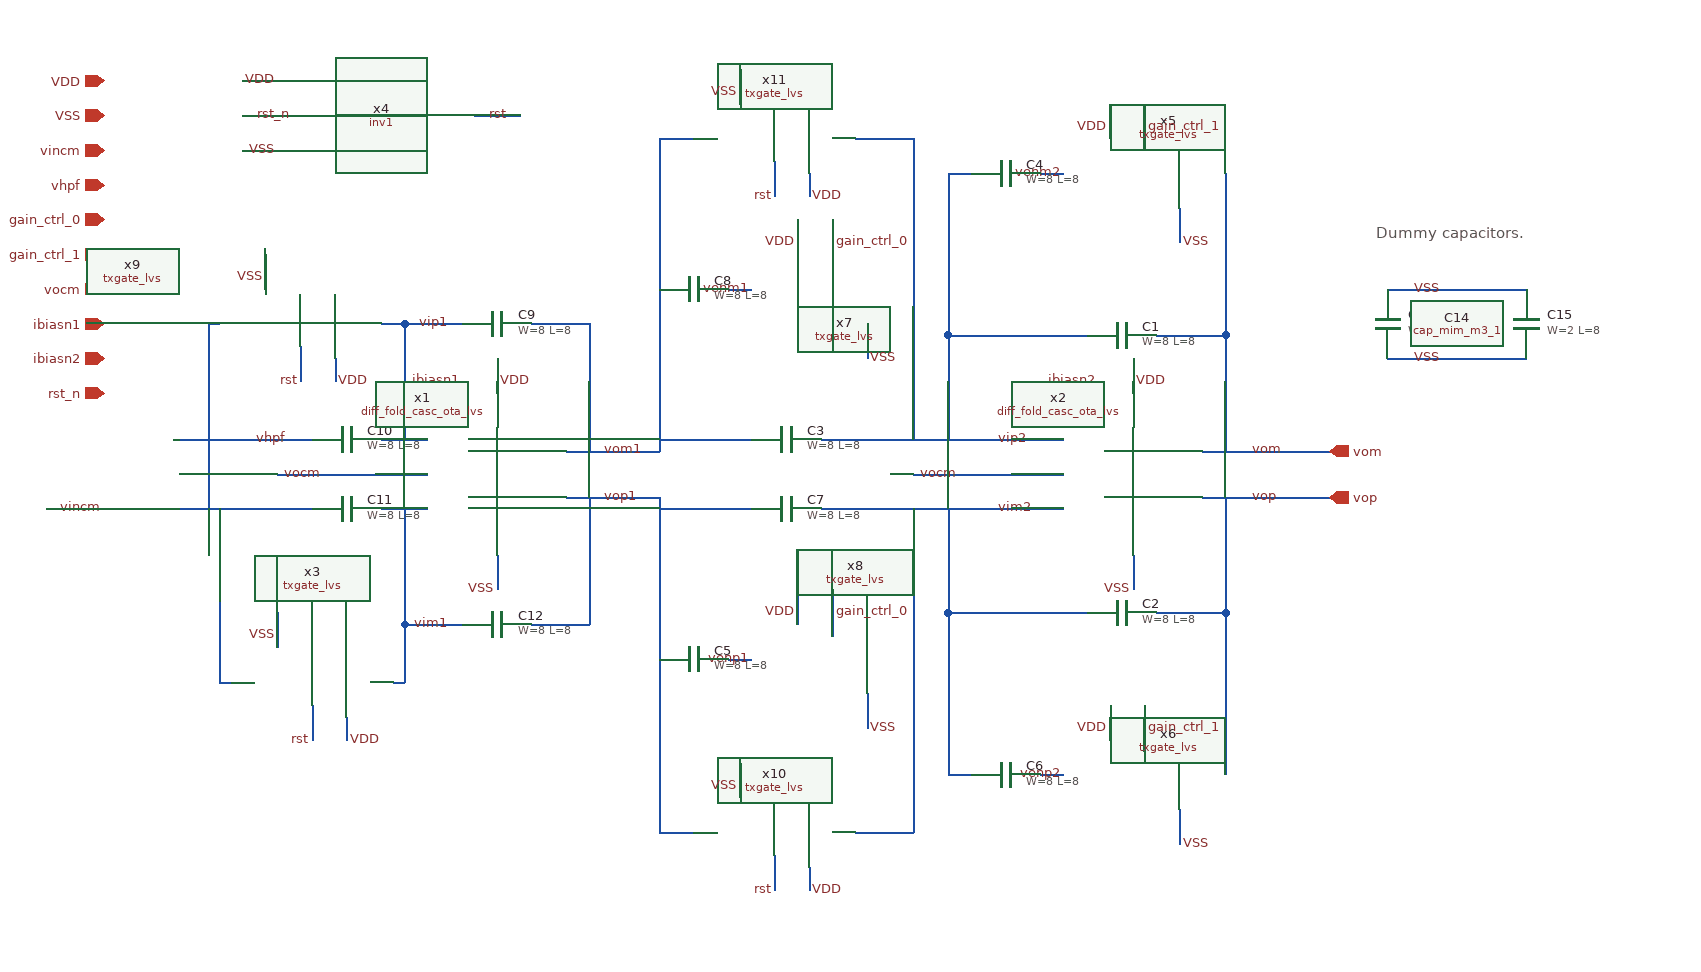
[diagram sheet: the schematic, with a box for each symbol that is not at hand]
v {xschem version=2.9.9 file_version=1.2 }
G {}
K {}
V {}
S {}
E {}
T {Dummy capacitors.} 1230 -710 0 0 0.4 0.4 {}
N 1040 -610 1100 -610 { lab=vom}
N 1100 -610 1100 -510 { lab=vom}
N 1080 -470 1190 -470 { lab=vop}
N 1080 -510 1190 -510 { lab=vom}
N 860 -610 980 -610 { lab=vip2}
N 860 -610 860 -520 { lab=vip2}
N 860 -750 880 -750 { lab=vip2}
N 860 -750 860 -610 { lab=vip2}
N 1100 -750 1100 -610 { lab=vom}
N 750 -520 960 -520 { lab=vip2}
N 830 -650 830 -520 { lab=vip2}
N 1040 -370 1100 -370 { lab=vop}
N 1100 -470 1100 -370 { lab=vop}
N 860 -370 980 -370 { lab=vim2}
N 860 -460 860 -370 { lab=vim2}
N 860 -230 880 -230 { lab=vim2}
N 860 -370 860 -230 { lab=vim2}
N 1100 -370 1100 -230 { lab=vop}
N 750 -460 960 -460 { lab=vim2}
N 830 -460 830 -330 { lab=vim2}
N 370 -520 410 -520 { lab=vip1}
N 370 -460 410 -460 { lab=vim1}
N 390 -460 390 -360 { lab=vim1}
N 390 -360 440 -360 { lab=vim1}
N 390 -620 390 -520 { lab=vip1}
N 390 -620 440 -620 { lab=vip1}
N 280 -490 410 -490 { lab=vocm}
N 500 -620 550 -620 { lab=vom1}
N 550 -620 550 -510 { lab=vom1}
N 500 -360 550 -360 { lab=vop1}
N 550 -470 550 -360 { lab=vop1}
N 530 -510 610 -510 { lab=vom1}
N 530 -470 610 -470 { lab=vop1}
N 190 -520 310 -520 { lab=vhpf}
N 80 -460 310 -460 { lab=vincm}
N 830 -490 960 -490 { lab=vocm}
N 610 -520 690 -520 { lab=vom1}
N 610 -460 690 -460 { lab=vop1}
N 610 -650 610 -510 { lab=vom1}
N 610 -470 610 -330 { lab=vop1}
N 940 -750 960 -750 { lab=venm2}
N 1030 -810 1030 -770 { lab=gain_ctrl_1}
N 1060 -720 1060 -690 { lab=VSS}
N 1000 -810 1000 -780 { lab=VDD}
N 940 -230 960 -230 { lab=venp2}
N 1030 -290 1030 -250 { lab=gain_ctrl_1}
N 1060 -200 1060 -170 { lab=VSS}
N 1000 -290 1000 -260 { lab=VDD}
N 760 -710 760 -670 { lab=gain_ctrl_0}
N 790 -620 790 -590 { lab=VSS}
N 730 -710 730 -680 { lab=VDD}
N 670 -650 690 -650 { lab=venm1}
N 760 -390 760 -350 { lab=gain_ctrl_0}
N 790 -300 790 -270 { lab=VSS}
N 730 -390 730 -360 { lab=VDD}
N 670 -330 690 -330 { lab=venp1}
N 400 -570 440 -570 { lab=ibiasn1}
N 470 -590 470 -560 { lab=VDD}
N 470 -420 470 -390 { lab=VSS}
N 950 -570 990 -570 { lab=ibiasn2}
N 1020 -590 1020 -560 { lab=VDD}
N 1020 -420 1020 -390 { lab=VSS}
N 1240 -650 1350 -650 { lab=VSS}
N 1240 -590 1350 -590 { lab=VSS}
N 380 -310 390 -310 { lab=vim1}
N 230 -310 240 -310 { lab=vincm}
N 280 -370 280 -340 { lab=VSS}
N 340 -280 340 -260 { lab=VDD}
N 310 -290 310 -260 { lab=rst}
N 450 -800 490 -800 { lab=rst}
N 250 -830 290 -830 { lab=VDD}
N 250 -770 290 -770 { lab=VSS}
N 250 -800 290 -800 { lab=rst_n}
N 390 -360 390 -310 { lab=vim1}
N 230 -460 230 -310 { lab=vincm}
N 370 -620 380 -620 { lab=vip1}
N 220 -620 230 -620 { lab=vincm}
N 270 -680 270 -650 { lab=VSS}
N 330 -590 330 -570 { lab=VDD}
N 300 -600 300 -570 { lab=rst}
N 380 -620 390 -620 { lab=vip1}
N 220 -620 220 -460 { lab=vincm}
N 780 -180 790 -180 { lab=vim2}
N 630 -180 640 -180 { lab=vop1}
N 680 -240 680 -210 { lab=VSS}
N 740 -150 740 -130 { lab=VDD}
N 710 -160 710 -130 { lab=rst}
N 790 -180 800 -180 { lab=vim2}
N 800 -180 830 -180 { lab=vim2}
N 830 -330 830 -180 { lab=vim2}
N 610 -180 630 -180 { lab=vop1}
N 610 -330 610 -180 { lab=vop1}
N 780 -780 790 -780 { lab=vip2}
N 630 -780 640 -780 { lab=vom1}
N 680 -840 680 -810 { lab=VSS}
N 740 -750 740 -730 { lab=VDD}
N 710 -760 710 -730 { lab=rst}
N 790 -780 800 -780 { lab=vip2}
N 800 -780 830 -780 { lab=vip2}
N 830 -780 830 -650 { lab=vip2}
N 610 -780 630 -780 { lab=vom1}
N 610 -780 610 -650 { lab=vom1}
N 1350 -650 1360 -650 {}
N 1350 -590 1360 -590 {}
C {devices/title.sym} 160 -30 0 0 {name=l1 author="Nikhil Poole"}
C {devices/lab_wire.sym} 1120 -510 0 1 {name=l7 sig_type=std_logic lab=vom}
C {devices/lab_wire.sym} 1120 -470 0 1 {name=l8 sig_type=std_logic lab=vop}
C {devices/lab_wire.sym} 430 -620 0 0 {name=l4 sig_type=std_logic lab=vip1}
C {devices/lab_wire.sym} 430 -360 2 1 {name=l5 sig_type=std_logic lab=vim1}
C {devices/lab_wire.sym} 130 -460 0 0 {name=l3 sig_type=std_logic lab=vincm}
C {devices/lab_wire.sym} 560 -510 0 1 {name=l30 sig_type=std_logic lab=vom1}
C {devices/lab_wire.sym} 560 -470 0 1 {name=l31 sig_type=std_logic lab=vop1}
C {devices/lab_wire.sym} 320 -490 0 0 {name=l33 sig_type=std_logic lab=vocm}
C {devices/lab_wire.sym} 870 -490 0 0 {name=l2 sig_type=std_logic lab=vocm}
C {devices/lab_wire.sym} 290 -520 0 0 {name=l29 sig_type=std_logic lab=vhpf}
C {devices/lab_wire.sym} 900 -460 0 1 {name=l34 sig_type=std_logic lab=vim2}
C {devices/lab_wire.sym} 900 -520 0 1 {name=l35 sig_type=std_logic lab=vip2}
C {/home/users/nhpoole/ee272b/ee272b_mixed_signal_mmwave_accelerator/designs/txgate_lvs.sym} 1030 -750 0 0 {name=x5}
C {devices/lab_wire.sym} 960 -750 0 0 {name=l25 sig_type=std_logic lab=venm2}
C {devices/lab_wire.sym} 1030 -790 0 1 {name=l27 sig_type=std_logic lab=gain_ctrl_1}
C {devices/lab_wire.sym} 1060 -690 0 1 {name=l39 sig_type=std_logic lab=VSS}
C {devices/lab_wire.sym} 1000 -790 0 0 {name=l40 sig_type=std_logic lab=VDD}
C {/home/users/nhpoole/ee272b/ee272b_mixed_signal_mmwave_accelerator/designs/txgate_lvs.sym} 1030 -230 0 0 {name=x6}
C {devices/lab_wire.sym} 960 -230 0 0 {name=l12 sig_type=std_logic lab=venp2}
C {devices/lab_wire.sym} 1030 -270 0 1 {name=l14 sig_type=std_logic lab=gain_ctrl_1}
C {devices/lab_wire.sym} 1060 -170 0 1 {name=l26 sig_type=std_logic lab=VSS}
C {devices/lab_wire.sym} 1000 -270 0 0 {name=l28 sig_type=std_logic lab=VDD}
C {/home/users/nhpoole/ee272b/ee272b_mixed_signal_mmwave_accelerator/designs/txgate_lvs.sym} 760 -650 0 0 {name=x7}
C {devices/lab_wire.sym} 760 -690 0 1 {name=l6 sig_type=std_logic lab=gain_ctrl_0}
C {devices/lab_wire.sym} 790 -590 0 1 {name=l11 sig_type=std_logic lab=VSS}
C {devices/lab_wire.sym} 730 -690 0 0 {name=l19 sig_type=std_logic lab=VDD}
C {devices/lab_wire.sym} 690 -650 0 0 {name=l20 sig_type=std_logic lab=venm1}
C {/home/users/nhpoole/ee272b/ee272b_mixed_signal_mmwave_accelerator/designs/txgate_lvs.sym} 760 -330 0 0 {name=x8}
C {devices/lab_wire.sym} 760 -370 0 1 {name=l15 sig_type=std_logic lab=gain_ctrl_0}
C {devices/lab_wire.sym} 790 -270 0 1 {name=l16 sig_type=std_logic lab=VSS}
C {devices/lab_wire.sym} 730 -370 0 0 {name=l21 sig_type=std_logic lab=VDD}
C {devices/lab_wire.sym} 690 -330 0 0 {name=l22 sig_type=std_logic lab=venp1}
C {devices/ipin.sym} 130 -830 0 0 {name=p1 lab=VDD}
C {devices/ipin.sym} 130 -800 0 0 {name=p2 lab=VSS}
C {devices/ipin.sym} 130 -770 0 0 {name=p3 lab=vincm}
C {devices/ipin.sym} 130 -740 0 0 {name=p4 lab=vhpf}
C {devices/ipin.sym} 130 -710 0 0 {name=p5 lab=gain_ctrl_0}
C {devices/ipin.sym} 130 -680 0 0 {name=p6 lab=gain_ctrl_1}
C {devices/ipin.sym} 130 -650 0 0 {name=p7 lab=vocm}
C {devices/ipin.sym} 130 -620 0 0 {name=p8 lab=ibiasn1}
C {devices/lab_wire.sym} 440 -570 0 0 {name=l9 sig_type=std_logic lab=ibiasn1}
C {devices/lab_wire.sym} 470 -390 0 0 {name=l13 sig_type=std_logic lab=VSS}
C {devices/lab_wire.sym} 470 -570 0 1 {name=l17 sig_type=std_logic lab=VDD}
C {devices/lab_wire.sym} 990 -570 0 0 {name=l18 sig_type=std_logic lab=ibiasn2}
C {devices/lab_wire.sym} 1020 -390 0 0 {name=l23 sig_type=std_logic lab=VSS}
C {devices/lab_wire.sym} 1020 -570 0 1 {name=l24 sig_type=std_logic lab=VDD}
C {sky130_fd_pr/cap_mim_m3_1.sym} 1010 -610 1 0 {name=C1 model=cap_mim_m3_1 W=8 L=8 MF=2 spiceprefix=X}
C {sky130_fd_pr/cap_mim_m3_1.sym} 1010 -370 1 0 {name=C2 model=cap_mim_m3_1 W=8 L=8 MF=2 spiceprefix=X}
C {sky130_fd_pr/cap_mim_m3_1.sym} 910 -750 1 0 {name=C4 model=cap_mim_m3_1 W=8 L=8 MF=6 spiceprefix=X}
C {sky130_fd_pr/cap_mim_m3_1.sym} 910 -230 1 0 {name=C6 model=cap_mim_m3_1 W=8 L=8 MF=6 spiceprefix=X}
C {sky130_fd_pr/cap_mim_m3_1.sym} 640 -330 1 0 {name=C5 model=cap_mim_m3_1 W=8 L=8 MF=4 spiceprefix=X}
C {sky130_fd_pr/cap_mim_m3_1.sym} 720 -460 1 0 {name=C7 model=cap_mim_m3_1 W=8 L=8 MF=4 spiceprefix=X}
C {sky130_fd_pr/cap_mim_m3_1.sym} 720 -520 1 0 {name=C3 model=cap_mim_m3_1 W=8 L=8 MF=4 spiceprefix=X}
C {sky130_fd_pr/cap_mim_m3_1.sym} 640 -650 1 0 {name=C8 model=cap_mim_m3_1 W=8 L=8 MF=4 spiceprefix=X}
C {sky130_fd_pr/cap_mim_m3_1.sym} 470 -620 1 0 {name=C9 model=cap_mim_m3_1 W=8 L=8 MF=4 spiceprefix=X}
C {sky130_fd_pr/cap_mim_m3_1.sym} 340 -520 1 0 {name=C10 model=cap_mim_m3_1 W=8 L=8 MF=4 spiceprefix=X}
C {sky130_fd_pr/cap_mim_m3_1.sym} 340 -460 1 0 {name=C11 model=cap_mim_m3_1 W=8 L=8 MF=4 spiceprefix=X}
C {sky130_fd_pr/cap_mim_m3_1.sym} 470 -360 1 0 {name=C12 model=cap_mim_m3_1 W=8 L=8 MF=4 spiceprefix=X}
C {sky130_fd_pr/cap_mim_m3_1.sym} 1240 -620 0 0 {name=C13 model=cap_mim_m3_1 W=12 L=2 MF=20 spiceprefix=X}
C {sky130_fd_pr/cap_mim_m3_1.sym} 1300 -620 0 0 {name=C14 model=cap_mim_m3_1 W=8 L=2 MF=22 spiceprefix=X}
C {sky130_fd_pr/cap_mim_m3_1.sym} 1360 -620 0 0 {name=C15 model=cap_mim_m3_1 W=2 L=8 MF=24 spiceprefix=X}
C {devices/lab_wire.sym} 1260 -650 0 1 {name=l10 sig_type=std_logic lab=VSS}
C {devices/lab_wire.sym} 1260 -590 2 0 {name=l32 sig_type=std_logic lab=VSS}
C {devices/opin.sym} 1190 -510 0 0 {name=p9 lab=vom}
C {devices/opin.sym} 1190 -470 0 0 {name=p10 lab=vop}
C {/home/users/nhpoole/ee272b/ee272b_mixed_signal_mmwave_accelerator/designs/diff_fold_casc_ota_lvs.sym} 470 -490 0 0 {name=x1}
C {/home/users/nhpoole/ee272b/ee272b_mixed_signal_mmwave_accelerator/designs/diff_fold_casc_ota_lvs.sym} 1020 -490 0 0 {name=x2}
C {devices/ipin.sym} 130 -590 0 0 {name=p11 lab=ibiasn2}
C {/home/users/nhpoole/ee272b/ee272b_mixed_signal_mmwave_accelerator/designs/txgate_lvs.sym} 310 -310 2 0 {name=x3}
C {devices/lab_wire.sym} 280 -350 0 0 {name=l36 sig_type=std_logic lab=VSS}
C {devices/lab_wire.sym} 340 -260 0 1 {name=l37 sig_type=std_logic lab=VDD}
C {devices/lab_wire.sym} 310 -260 0 0 {name=l38 sig_type=std_logic lab=rst}
C {/home/users/nhpoole/ee272b/ee272b_mixed_signal_mmwave_accelerator/designs/inv1.sym} 340 -800 0 0 {name=x4}
C {devices/lab_wire.sym} 460 -800 0 1 {name=l41 sig_type=std_logic lab=rst}
C {devices/lab_wire.sym} 260 -800 0 1 {name=l42 sig_type=std_logic lab=rst_n}
C {devices/lab_wire.sym} 280 -830 0 0 {name=l43 sig_type=std_logic lab=VDD}
C {devices/lab_wire.sym} 280 -770 0 0 {name=l44 sig_type=std_logic lab=VSS}
C {devices/ipin.sym} 130 -560 0 0 {name=p12 lab=rst_n}
C {/home/users/nhpoole/ee272b/ee272b_mixed_signal_mmwave_accelerator/designs/txgate_lvs.sym} 300 -620 2 0 {name=x9}
C {devices/lab_wire.sym} 270 -660 0 0 {name=l45 sig_type=std_logic lab=VSS}
C {devices/lab_wire.sym} 330 -570 0 1 {name=l46 sig_type=std_logic lab=VDD}
C {devices/lab_wire.sym} 300 -570 0 0 {name=l47 sig_type=std_logic lab=rst}
C {/home/users/nhpoole/ee272b/ee272b_mixed_signal_mmwave_accelerator/designs/txgate_lvs.sym} 710 -180 2 0 {name=x10}
C {devices/lab_wire.sym} 680 -220 0 0 {name=l48 sig_type=std_logic lab=VSS}
C {devices/lab_wire.sym} 740 -130 0 1 {name=l49 sig_type=std_logic lab=VDD}
C {devices/lab_wire.sym} 710 -130 0 0 {name=l50 sig_type=std_logic lab=rst}
C {/home/users/nhpoole/ee272b/ee272b_mixed_signal_mmwave_accelerator/designs/txgate_lvs.sym} 710 -780 2 0 {name=x11}
C {devices/lab_wire.sym} 680 -820 0 0 {name=l51 sig_type=std_logic lab=VSS}
C {devices/lab_wire.sym} 740 -730 0 1 {name=l52 sig_type=std_logic lab=VDD}
C {devices/lab_wire.sym} 710 -730 0 0 {name=l53 sig_type=std_logic lab=rst}
